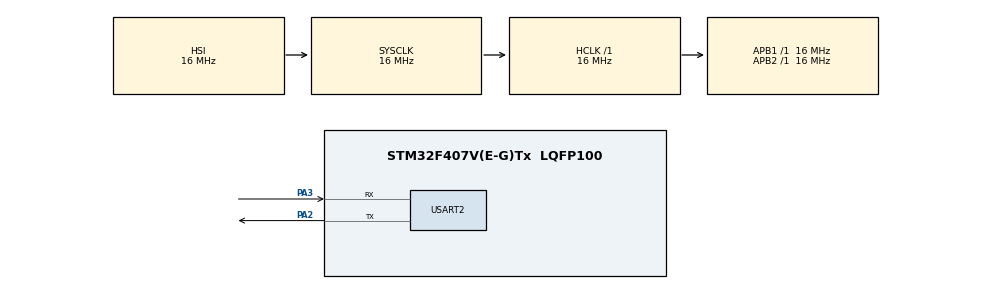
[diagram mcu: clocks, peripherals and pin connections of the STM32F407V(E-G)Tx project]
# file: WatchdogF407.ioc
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FREERTOS.Tasks01=defaultTask,24,128,StartDefaultTask,Default,NULL,Dynamic,NULL,NULL
Mcu.Family=STM32F4
Mcu.Name=STM32F407V(E-G)Tx
Mcu.Package=LQFP100
NVIC.PriorityGroup=NVIC_PRIORITYGROUP_4
NVIC.TIM1_UP_TIM10_IRQn=true\:15\:0\:false\:false\:true\:false\:false\:true\:true
NVIC.TimeBase=TIM1_UP_TIM10_IRQn
NVIC.TimeBaseIP=TIM1
PA2.Mode=Asynchronous
PA2.Signal=USART2_TX
PA3.Mode=Asynchronous
PA3.Signal=USART2_RX
ProjectManager.HeapSize=0x200
ProjectManager.StackSize=0x400
ProjectManager.TargetToolchain=STM32CubeIDE
RCC.AHBFreq_Value=16000000
RCC.APB1Freq_Value=16000000
RCC.APB2Freq_Value=16000000
RCC.CortexFreq_Value=16000000
RCC.HSE_VALUE=25000000
RCC.HSI_VALUE=16000000
RCC.LSE_VALUE=32768
RCC.SYSCLKFreq_VALUE=16000000
RCC.VCOOutputFreq_Value=192000000
USART2.VirtualMode=VM_ASYNC
VP_FREERTOS_VS_CMSIS_V2.Mode=CMSIS_V2
VP_SYS_VS_tim1.Mode=TIM1
board=custom

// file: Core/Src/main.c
/* USER CODE BEGIN Includes */
#include "FreeRTOS.h"
#include "task.h"
#include "event_groups.h"

void MX_FREERTOS_Init(void);   /* ← add this line */
/* USER CODE END Includes *//* USER CODE BEGIN Header */
/**
  ******************************************************************************
  * @file           : main.c
  * @brief          : Main program body
  ******************************************************************************
  * @attention
  *
  * Copyright (c) 2026 STMicroelectronics.
  * All rights reserved.
  *
  * This software is licensed under terms that can be found in the LICENSE file
  * in the root directory of this software component.
  * If no LICENSE file comes with this software, it is provided AS-IS.
  *
  ******************************************************************************
  */
/* USER CODE END Header */
/* Includes ------------------------------------------------------------------*/
#include "main.h"
#include "cmsis_os.h"

/* Private includes ----------------------------------------------------------*/
/* USER CODE BEGIN Includes */

/* USER CODE END Includes */

UART_HandleTypeDef huart2;

/* Definitions for defaultTask */
osThreadId_t defaultTaskHandle;
const osThreadAttr_t defaultTask_attributes = {
  .name = "defaultTask",
  .stack_size = 128 * 4,
  .priority = (osPriority_t) osPriorityNormal,
};

void SystemClock_Config(void);
static void MX_GPIO_Init(void);
static void MX_USART2_UART_Init(void);
void StartDefaultTask(void *argument);

int main(void)
{

  /* MCU Configuration--------------------------------------------------------*/

  /* Reset of all peripherals, Initializes the Flash interface and the Systick. */
  HAL_Init();

  /* Configure the system clock */
  SystemClock_Config();

  /* Initialize all configured peripherals */
  MX_GPIO_Init();
  MX_USART2_UART_Init();
  /* USER CODE BEGIN 2 */
  __HAL_RCC_GPIOD_CLK_ENABLE();
  GPIO_InitTypeDef GPIO_InitStruct = {0};
  GPIO_InitStruct.Pin = GPIO_PIN_12|GPIO_PIN_13|GPIO_PIN_14|GPIO_PIN_15;
  GPIO_InitStruct.Mode = GPIO_MODE_OUTPUT_PP;
  GPIO_InitStruct.Pull = GPIO_NOPULL;
  GPIO_InitStruct.Speed = GPIO_SPEED_FREQ_LOW;
  HAL_GPIO_Init(GPIOD, &GPIO_InitStruct);

  // Test - turn ALL LEDs ON

  /* USER CODE END 2 */

  /* Init scheduler */
  osKernelInitialize();

  /* Create the thread(s) */
  /* creation of defaultTask */
  defaultTaskHandle = osThreadNew(StartDefaultTask, NULL, &defaultTask_attributes);

  /* USER CODE BEGIN RTOS_THREADS */
  MX_FREERTOS_Init();
  /* USER CODE END RTOS_THREADS */

  /* Start scheduler */
  osKernelStart();

  /* We should never get here as control is now taken by the scheduler */

  /* Infinite loop */
  while (1)
  {

  }
}

void SystemClock_Config(void)
{
  RCC_OscInitTypeDef RCC_OscInitStruct = {0};
  RCC_ClkInitTypeDef RCC_ClkInitStruct = {0};

  /** Configure the main internal regulator output voltage
  */
  __HAL_RCC_PWR_CLK_ENABLE();
  __HAL_PWR_VOLTAGESCALING_CONFIG(PWR_REGULATOR_VOLTAGE_SCALE1);

  /** Initializes the RCC Oscillators according to the specified parameters
  * in the RCC_OscInitTypeDef structure.
  */
  RCC_OscInitStruct.OscillatorType = RCC_OSCILLATORTYPE_HSI;
  RCC_OscInitStruct.HSIState = RCC_HSI_ON;
  RCC_OscInitStruct.HSICalibrationValue = RCC_HSICALIBRATION_DEFAULT;
  RCC_OscInitStruct.PLL.PLLState = RCC_PLL_NONE;
  if (HAL_RCC_OscConfig(&RCC_OscInitStruct) != HAL_OK)
  {
    Error_Handler();
  }

  /** Initializes the CPU, AHB and APB buses clocks
  */
  RCC_ClkInitStruct.ClockType = RCC_CLOCKTYPE_HCLK|RCC_CLOCKTYPE_SYSCLK
                              |RCC_CLOCKTYPE_PCLK1|RCC_CLOCKTYPE_PCLK2;
  RCC_ClkInitStruct.SYSCLKSource = RCC_SYSCLKSOURCE_HSI;
  RCC_ClkInitStruct.AHBCLKDivider = RCC_SYSCLK_DIV1;
  RCC_ClkInitStruct.APB1CLKDivider = RCC_HCLK_DIV1;
  RCC_ClkInitStruct.APB2CLKDivider = RCC_HCLK_DIV1;

  if (HAL_RCC_ClockConfig(&RCC_ClkInitStruct, FLASH_LATENCY_0) != HAL_OK)
  {
    Error_Handler();
  }
}

static void MX_USART2_UART_Init(void)
{

  huart2.Instance = USART2;
  huart2.Init.BaudRate = 115200;
  huart2.Init.WordLength = UART_WORDLENGTH_8B;
  huart2.Init.StopBits = UART_STOPBITS_1;
  huart2.Init.Parity = UART_PARITY_NONE;
  huart2.Init.Mode = UART_MODE_TX_RX;
  huart2.Init.HwFlowCtl = UART_HWCONTROL_NONE;
  huart2.Init.OverSampling = UART_OVERSAMPLING_16;
  if (HAL_UART_Init(&huart2) != HAL_OK)
  {
    Error_Handler();
  }

}

static void MX_GPIO_Init(void)
{
  GPIO_InitTypeDef GPIO_InitStruct = {0};

  /* GPIO Ports Clock Enable */
  __HAL_RCC_GPIOA_CLK_ENABLE();
  __HAL_RCC_GPIOD_CLK_ENABLE();

  /* Set LED pins low initially */
  HAL_GPIO_WritePin(GPIOD, GPIO_PIN_12|GPIO_PIN_13|GPIO_PIN_14|GPIO_PIN_15, GPIO_PIN_RESET);

  /* Configure LED pins as output */
  GPIO_InitStruct.Pin = GPIO_PIN_12|GPIO_PIN_13|GPIO_PIN_14|GPIO_PIN_15;
  GPIO_InitStruct.Mode = GPIO_MODE_OUTPUT_PP;
  GPIO_InitStruct.Pull = GPIO_NOPULL;
  GPIO_InitStruct.Speed = GPIO_SPEED_FREQ_LOW;
  HAL_GPIO_Init(GPIOD, &GPIO_InitStruct);
}

void StartDefaultTask(void *argument)
{
  for(;;)
  {
    osDelay(1);
  }
}

void HAL_TIM_PeriodElapsedCallback(TIM_HandleTypeDef *htim)
{
  if (htim->Instance == TIM1)
  {
    HAL_IncTick();
  }
}

void Error_Handler(void)
{
  __disable_irq();
  while (1)
  {
  }
}

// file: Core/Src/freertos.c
#include "FreeRTOS.h"
#include "task.h"
#include "main.h"
#include "cmsis_os.h"
#include "event_groups.h"

#define BIT_MIC_TASK    (1 << 0)
#define BIT_ACCEL_TASK  (1 << 1)
#define BIT_ADC_TASK    (1 << 2)
#define BIT_UART_TASK   (1 << 3)
#define ALL_BITS (BIT_MIC_TASK | BIT_ACCEL_TASK | BIT_ADC_TASK | BIT_UART_TASK)

EventGroupHandle_t xTaskEventGroup;

void MicTask(void *argument) {
    for(;;) {
        HAL_GPIO_TogglePin(GPIOD, GPIO_PIN_12);
        xEventGroupSetBits(xTaskEventGroup, BIT_MIC_TASK);
        osDelay(400);
    }
}

void AccelTask(void *argument) {
    for(;;) {
//         while(1);  // uncomment to simulate failure
        HAL_GPIO_TogglePin(GPIOD, GPIO_PIN_13);
        xEventGroupSetBits(xTaskEventGroup, BIT_ACCEL_TASK);
        osDelay(700);
    }
}

void ADCTask(void *argument) {
    for(;;) {
//    	vTaskDelay(portMAX_DELAY);
        HAL_GPIO_TogglePin(GPIOD, GPIO_PIN_14);
        xEventGroupSetBits(xTaskEventGroup, BIT_ADC_TASK);
        osDelay(1100);
    }
}

void UARTTask(void *argument) {
    for(;;) {
        HAL_GPIO_TogglePin(GPIOD, GPIO_PIN_15);
        xEventGroupSetBits(xTaskEventGroup, BIT_UART_TASK);
        osDelay(1600);
    }
}

void WatchdogTask(void *argument) {
    EventBits_t bits;
    osDelay(2000);
    for(;;) {
        xEventGroupClearBits(xTaskEventGroup, ALL_BITS);
        bits = xEventGroupWaitBits(xTaskEventGroup,
                                   ALL_BITS, pdTRUE, pdTRUE,
                                   pdMS_TO_TICKS(2000));
        if ((bits & ALL_BITS) != ALL_BITS) {
            uint16_t failedPins = 0;
            if (!(bits & BIT_MIC_TASK))   failedPins |= GPIO_PIN_12;
            if (!(bits & BIT_ACCEL_TASK)) failedPins |= GPIO_PIN_13;
            if (!(bits & BIT_ADC_TASK))   failedPins |= GPIO_PIN_14;
            if (!(bits & BIT_UART_TASK))  failedPins |= GPIO_PIN_15;
            for(int i = 0; i < 10; i++) {
                HAL_GPIO_WritePin(GPIOD, failedPins, GPIO_PIN_SET);
                osDelay(100);
                HAL_GPIO_WritePin(GPIOD, failedPins, GPIO_PIN_RESET);
                osDelay(100);
            }
        }
        osDelay(500);
    }
}

// NO vTaskStartScheduler() here — main.c handles it via osKernelStart()
void MX_FREERTOS_Init(void) {
    xTaskEventGroup = xEventGroupCreate();
    xTaskCreate(MicTask,      "Mic",   128, NULL, 1, NULL);
    xTaskCreate(AccelTask,    "Accel", 128, NULL, 2, NULL);
    xTaskCreate(ADCTask,      "ADC",   128, NULL, 4, NULL);
    xTaskCreate(UARTTask,     "UART",  128, NULL, 3, NULL);
    xTaskCreate(WatchdogTask, "WDG",   256, NULL, 5, NULL);
}
